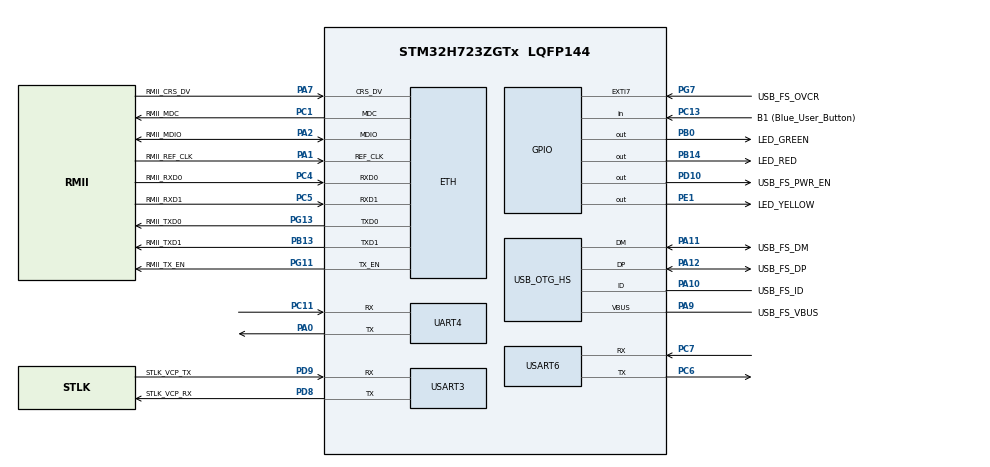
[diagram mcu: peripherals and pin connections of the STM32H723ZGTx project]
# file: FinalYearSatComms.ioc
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ETH.MediaInterface=HAL_ETH_RMII_MODE
Mcu.Family=STM32H7
Mcu.Name=STM32H723ZGTx
Mcu.Package=LQFP144
NVIC.PriorityGroup=NVIC_PRIORITYGROUP_4
PA0.Mode=Asynchronous
PA0.Signal=UART4_TX
PA1.GPIO_Label=RMII_REF_CLK
PA1.Mode=RMII
PA1.Signal=ETH_REF_CLK
PA10.GPIO_Label=USB_FS_ID
PA10.Mode=OTG/Dual-Role-Device-FS
PA10.Signal=USB_OTG_HS_ID
PA11.GPIO_Label=USB_FS_DM
PA11.Mode=OTG/Dual-Role-Device-FS
PA11.Signal=USB_OTG_HS_DM
PA12.GPIO_Label=USB_FS_DP
PA12.Mode=OTG/Dual-Role-Device-FS
PA12.Signal=USB_OTG_HS_DP
PA13(JTMS/SWDIO).GPIO_Label=SWDIO
PA13(JTMS/SWDIO).Mode=Trace_Asynchronous_SW
PA13(JTMS/SWDIO).Signal=DEBUG_JTMS-SWDIO
PA14(JTCK/SWCLK).GPIO_Label=SWCLK
PA14(JTCK/SWCLK).Mode=Trace_Asynchronous_SW
PA14(JTCK/SWCLK).Signal=DEBUG_JTCK-SWCLK
PA2.GPIO_Label=RMII_MDIO
PA2.Mode=RMII
PA2.Signal=ETH_MDIO
PA7.GPIO_Label=RMII_CRS_DV
PA7.Mode=RMII
PA7.Signal=ETH_CRS_DV
PA9.GPIO_Label=USB_FS_VBUS
PA9.Mode=Activate_VBUS_FS
PA9.Signal=USB_OTG_HS_VBUS
PB0.GPIO_Label=LED_GREEN
PB0.Signal=GPIO_Output
PB13.GPIO_Label=RMII_TXD1
PB13.Mode=RMII
PB13.Signal=ETH_TXD1
PB14.GPIO_Label=LED_RED
PB14.Signal=GPIO_Output
PB3(JTDO/TRACESWO).GPIO_Label=SWO
PB3(JTDO/TRACESWO).Mode=Trace_Asynchronous_SW
PB3(JTDO/TRACESWO).Signal=DEBUG_JTDO-SWO
PC1.GPIO_Label=RMII_MDC
PC1.Mode=RMII
PC1.Signal=ETH_MDC
PC11.Mode=Asynchronous
PC11.Signal=UART4_RX
PC13.GPIO_Label=B1 (Blue_User_Button)
PC13.Signal=GPIO_Input
PC14-OSC32_IN.Mode=LSE-External-Oscillator
PC14-OSC32_IN.Signal=RCC_OSC32_IN
PC15-OSC32_OUT.Mode=LSE-External-Oscillator
PC15-OSC32_OUT.Signal=RCC_OSC32_OUT
PC4.GPIO_Label=RMII_RXD0
PC4.Mode=RMII
PC4.Signal=ETH_RXD0
PC5.GPIO_Label=RMII_RXD1
PC5.Mode=RMII
PC5.Signal=ETH_RXD1
PC6.Mode=Asynchronous
PC6.Signal=USART6_TX
PC7.Mode=Asynchronous
PC7.Signal=USART6_RX
PD10.GPIO_Label=USB_FS_PWR_EN
PD10.Signal=GPIO_Output
PD8.GPIO_Label=STLK_VCP_RX
PD8.Mode=Asynchronous
PD8.Signal=USART3_TX
PD9.GPIO_Label=STLK_VCP_TX
PD9.Mode=Asynchronous
PD9.Signal=USART3_RX
PE1.GPIO_Label=LED_YELLOW
PE1.Signal=GPIO_Output
PG11.GPIO_Label=RMII_TX_EN
PG11.Mode=RMII
PG11.Signal=ETH_TX_EN
PG13.GPIO_Label=RMII_TXD0
PG13.Mode=RMII
PG13.Signal=ETH_TXD0
PG7.GPIO_Label=USB_FS_OVCR
PG7.Signal=GPXTI7
PH0-OSC_IN.GPIO_Label=MCO
PH0-OSC_IN.Mode=HSE-External-Oscillator
PH0-OSC_IN.Signal=RCC_OSC_IN
PH1-OSC_OUT.Mode=HSE-External-Oscillator
PH1-OSC_OUT.Signal=RCC_OSC_OUT
ProjectManager.HeapSize=0x200
ProjectManager.StackSize=0x400
ProjectManager.TargetToolchain=STM32CubeIDE
RCC.ADCFreq_Value=76000000
RCC.APB1Freq_Value=2000000
RCC.APB2Freq_Value=2000000
RCC.APB3Freq_Value=2000000
RCC.APB4Freq_Value=2000000
RCC.CortexFreq_Value=8000000
RCC.D1CPRE=1
RCC.D1PPRE=RCC_APB3_DIV2
RCC.D2PPRE1=RCC_APB1_DIV2
RCC.D2PPRE2=RCC_APB2_DIV2
RCC.D3PPRE=RCC_APB4_DIV2
RCC.DIVM2=1
RCC.DIVN2=19
RCC.DIVQ1=4
RCC.HCLKFreq_Value=4000000
RCC.HPRE=RCC_HCLK_DIV2
RCC.HSE_VALUE=8000000
RCC.PLL2FRACN=0
RCC.PLL3FRACN=0
RCC.SYSCLKFreq_VALUE=8000000
RCC.SYSCLKSource=RCC_SYSCLKSOURCE_PLLCLK
RCC.USBCLockSelection=RCC_USBCLKSOURCE_HSI48
RCC.USBFreq_Value=48000000
USART3.VirtualMode-Asynchronous=VM_ASYNC
USART6.VirtualMode-Asynchronous=VM_ASYNC
board=NUCLEO-H723ZG

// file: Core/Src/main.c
/* USER CODE BEGIN Header */
/**
  ******************************************************************************
  * @file           : main.c
  * @brief          : Main program body
  ******************************************************************************
  * @attention
  *
  * Copyright (c) 2024 STMicroelectronics.
  * All rights reserved.
  *
  * This software is licensed under terms that can be found in the LICENSE file
  * in the root directory of this software component.
  * If no LICENSE file comes with this software, it is provided AS-IS.
  *
  ******************************************************************************
  */
/* USER CODE END Header */
#include "main.h"
#include "string.h"
#include "stdio.h"
#if defined ( __ICCARM__ ) /*!< IAR Compiler */
#pragma location=0x30000000
ETH_DMADescTypeDef  DMARxDscrTab[ETH_RX_DESC_CNT]; /* Ethernet Rx DMA Descriptors */
#pragma location=0x30000200
ETH_DMADescTypeDef  DMATxDscrTab[ETH_TX_DESC_CNT]; /* Ethernet Tx DMA Descriptors */

#elif defined ( __CC_ARM )  /* MDK ARM Compiler */

__attribute__((at(0x30000000))) ETH_DMADescTypeDef  DMARxDscrTab[ETH_RX_DESC_CNT]; /* Ethernet Rx DMA Descriptors */
__attribute__((at(0x30000200))) ETH_DMADescTypeDef  DMATxDscrTab[ETH_TX_DESC_CNT]; /* Ethernet Tx DMA Descriptors */

#elif defined ( __GNUC__ ) /* GNU Compiler */

ETH_DMADescTypeDef DMARxDscrTab[ETH_RX_DESC_CNT] __attribute__((section(".RxDecripSection"))); /* Ethernet Rx DMA Descriptors */
ETH_DMADescTypeDef DMATxDscrTab[ETH_TX_DESC_CNT] __attribute__((section(".TxDecripSection")));   /* Ethernet Tx DMA Descriptors */
#endif

ETH_TxPacketConfig TxConfig;

ETH_HandleTypeDef heth;

UART_HandleTypeDef huart4;
UART_HandleTypeDef huart3;
UART_HandleTypeDef huart6;

void SystemClock_Config(void);
static void MX_GPIO_Init(void);
static void MX_ETH_Init(void);
static void MX_USART3_UART_Init(void);
static void MX_USB_OTG_HS_USB_Init(void);
static void MX_UART4_Init(void);
static void MX_USART6_UART_Init(void);

int _write(int file,char *ptr, int len)
{
	int i=0;
	for (i=0; i<len;i++)
		ITM_SendChar((*ptr++));
	return len;
}
uint8_t Data=0;
int main(void)
{

  HAL_Init();

  SystemClock_Config();

  MX_GPIO_Init();
  MX_ETH_Init();
  MX_USART3_UART_Init();
  MX_USB_OTG_HS_USB_Init();
  MX_UART4_Init();
  MX_USART6_UART_Init();

  while (1)
  {
	  printf("%d\n",Data);
	  Data++;
	  HAL_Delay(1000);
  }
  /* USER CODE END 3 */
}

void SystemClock_Config(void)
{
  RCC_OscInitTypeDef RCC_OscInitStruct = {0};
  RCC_ClkInitTypeDef RCC_ClkInitStruct = {0};

  /** Supply configuration update enable
  */
  HAL_PWREx_ConfigSupply(PWR_LDO_SUPPLY);

  /** Configure the main internal regulator output voltage
  */
  __HAL_PWR_VOLTAGESCALING_CONFIG(PWR_REGULATOR_VOLTAGE_SCALE3);

  while(!__HAL_PWR_GET_FLAG(PWR_FLAG_VOSRDY)) {}

  /** Initializes the RCC Oscillators according to the specified parameters
  * in the RCC_OscInitTypeDef structure.
  */
  RCC_OscInitStruct.OscillatorType = RCC_OSCILLATORTYPE_HSI48|RCC_OSCILLATORTYPE_HSI;
  RCC_OscInitStruct.HSIState = RCC_HSI_DIV1;
  RCC_OscInitStruct.HSICalibrationValue = 64;
  RCC_OscInitStruct.HSI48State = RCC_HSI48_ON;
  RCC_OscInitStruct.PLL.PLLState = RCC_PLL_ON;
  RCC_OscInitStruct.PLL.PLLSource = RCC_PLLSOURCE_HSI;
  RCC_OscInitStruct.PLL.PLLM = 32;
  RCC_OscInitStruct.PLL.PLLN = 129;
  RCC_OscInitStruct.PLL.PLLP = 2;
  RCC_OscInitStruct.PLL.PLLQ = 4;
  RCC_OscInitStruct.PLL.PLLR = 2;
  RCC_OscInitStruct.PLL.PLLRGE = RCC_PLL1VCIRANGE_1;
  RCC_OscInitStruct.PLL.PLLVCOSEL = RCC_PLL1VCOWIDE;
  RCC_OscInitStruct.PLL.PLLFRACN = 0;
  if (HAL_RCC_OscConfig(&RCC_OscInitStruct) != HAL_OK)
  {
    Error_Handler();
  }

  /** Initializes the CPU, AHB and APB buses clocks
  */
  RCC_ClkInitStruct.ClockType = RCC_CLOCKTYPE_HCLK|RCC_CLOCKTYPE_SYSCLK
                              |RCC_CLOCKTYPE_PCLK1|RCC_CLOCKTYPE_PCLK2
                              |RCC_CLOCKTYPE_D3PCLK1|RCC_CLOCKTYPE_D1PCLK1;
  RCC_ClkInitStruct.SYSCLKSource = RCC_SYSCLKSOURCE_PLLCLK;
  RCC_ClkInitStruct.SYSCLKDivider = 1;
  RCC_ClkInitStruct.AHBCLKDivider = RCC_HCLK_DIV2;
  RCC_ClkInitStruct.APB3CLKDivider = RCC_APB3_DIV2;
  RCC_ClkInitStruct.APB1CLKDivider = RCC_APB1_DIV2;
  RCC_ClkInitStruct.APB2CLKDivider = RCC_APB2_DIV2;
  RCC_ClkInitStruct.APB4CLKDivider = RCC_APB4_DIV2;

  if (HAL_RCC_ClockConfig(&RCC_ClkInitStruct, FLASH_LATENCY_0) != HAL_OK)
  {
    Error_Handler();
  }
}

static void MX_ETH_Init(void)
{

   static uint8_t MACAddr[6];

  heth.Instance = ETH;
  MACAddr[0] = 0x00;
  MACAddr[1] = 0x80;
  MACAddr[2] = 0xE1;
  MACAddr[3] = 0x00;
  MACAddr[4] = 0x00;
  MACAddr[5] = 0x00;
  heth.Init.MACAddr = &MACAddr[0];
  heth.Init.MediaInterface = HAL_ETH_RMII_MODE;
  heth.Init.TxDesc = DMATxDscrTab;
  heth.Init.RxDesc = DMARxDscrTab;
  heth.Init.RxBuffLen = 1524;

  if (HAL_ETH_Init(&heth) != HAL_OK)
  {
    Error_Handler();
  }

  memset(&TxConfig, 0 , sizeof(ETH_TxPacketConfig));
  TxConfig.Attributes = ETH_TX_PACKETS_FEATURES_CSUM | ETH_TX_PACKETS_FEATURES_CRCPAD;
  TxConfig.ChecksumCtrl = ETH_CHECKSUM_IPHDR_PAYLOAD_INSERT_PHDR_CALC;
  TxConfig.CRCPadCtrl = ETH_CRC_PAD_INSERT;

}

static void MX_UART4_Init(void)
{

  huart4.Instance = UART4;
  huart4.Init.BaudRate = 115200;
  huart4.Init.WordLength = UART_WORDLENGTH_8B;
  huart4.Init.StopBits = UART_STOPBITS_1;
  huart4.Init.Parity = UART_PARITY_NONE;
  huart4.Init.Mode = UART_MODE_TX_RX;
  huart4.Init.HwFlowCtl = UART_HWCONTROL_NONE;
  huart4.Init.OverSampling = UART_OVERSAMPLING_16;
  huart4.Init.OneBitSampling = UART_ONE_BIT_SAMPLE_DISABLE;
  huart4.Init.ClockPrescaler = UART_PRESCALER_DIV1;
  huart4.AdvancedInit.AdvFeatureInit = UART_ADVFEATURE_NO_INIT;
  if (HAL_UART_Init(&huart4) != HAL_OK)
  {
    Error_Handler();
  }
  if (HAL_UARTEx_SetTxFifoThreshold(&huart4, UART_TXFIFO_THRESHOLD_1_8) != HAL_OK)
  {
    Error_Handler();
  }
  if (HAL_UARTEx_SetRxFifoThreshold(&huart4, UART_RXFIFO_THRESHOLD_1_8) != HAL_OK)
  {
    Error_Handler();
  }
  if (HAL_UARTEx_DisableFifoMode(&huart4) != HAL_OK)
  {
    Error_Handler();
  }

}

static void MX_USART3_UART_Init(void)
{

  huart3.Instance = USART3;
  huart3.Init.BaudRate = 115200;
  huart3.Init.WordLength = UART_WORDLENGTH_8B;
  huart3.Init.StopBits = UART_STOPBITS_1;
  huart3.Init.Parity = UART_PARITY_NONE;
  huart3.Init.Mode = UART_MODE_TX_RX;
  huart3.Init.HwFlowCtl = UART_HWCONTROL_NONE;
  huart3.Init.OverSampling = UART_OVERSAMPLING_16;
  huart3.Init.OneBitSampling = UART_ONE_BIT_SAMPLE_DISABLE;
  huart3.Init.ClockPrescaler = UART_PRESCALER_DIV1;
  huart3.AdvancedInit.AdvFeatureInit = UART_ADVFEATURE_NO_INIT;
  if (HAL_UART_Init(&huart3) != HAL_OK)
  {
    Error_Handler();
  }
  if (HAL_UARTEx_SetTxFifoThreshold(&huart3, UART_TXFIFO_THRESHOLD_1_8) != HAL_OK)
  {
    Error_Handler();
  }
  if (HAL_UARTEx_SetRxFifoThreshold(&huart3, UART_RXFIFO_THRESHOLD_1_8) != HAL_OK)
  {
    Error_Handler();
  }
  if (HAL_UARTEx_DisableFifoMode(&huart3) != HAL_OK)
  {
    Error_Handler();
  }

}

static void MX_USART6_UART_Init(void)
{

  huart6.Instance = USART6;
  huart6.Init.BaudRate = 115200;
  huart6.Init.WordLength = UART_WORDLENGTH_8B;
  huart6.Init.StopBits = UART_STOPBITS_1;
  huart6.Init.Parity = UART_PARITY_NONE;
  huart6.Init.Mode = UART_MODE_TX_RX;
  huart6.Init.HwFlowCtl = UART_HWCONTROL_NONE;
  huart6.Init.OverSampling = UART_OVERSAMPLING_16;
  huart6.Init.OneBitSampling = UART_ONE_BIT_SAMPLE_DISABLE;
  huart6.Init.ClockPrescaler = UART_PRESCALER_DIV1;
  huart6.AdvancedInit.AdvFeatureInit = UART_ADVFEATURE_NO_INIT;
  if (HAL_UART_Init(&huart6) != HAL_OK)
  {
    Error_Handler();
  }
  if (HAL_UARTEx_SetTxFifoThreshold(&huart6, UART_TXFIFO_THRESHOLD_1_8) != HAL_OK)
  {
    Error_Handler();
  }
  if (HAL_UARTEx_SetRxFifoThreshold(&huart6, UART_RXFIFO_THRESHOLD_1_8) != HAL_OK)
  {
    Error_Handler();
  }
  if (HAL_UARTEx_DisableFifoMode(&huart6) != HAL_OK)
  {
    Error_Handler();
  }

}

static void MX_USB_OTG_HS_USB_Init(void)
{

}

static void MX_GPIO_Init(void)
{
  GPIO_InitTypeDef GPIO_InitStruct = {0};

  /* GPIO Ports Clock Enable */
  __HAL_RCC_GPIOC_CLK_ENABLE();
  __HAL_RCC_GPIOH_CLK_ENABLE();
  __HAL_RCC_GPIOA_CLK_ENABLE();
  __HAL_RCC_GPIOB_CLK_ENABLE();
  __HAL_RCC_GPIOD_CLK_ENABLE();
  __HAL_RCC_GPIOG_CLK_ENABLE();
  __HAL_RCC_GPIOE_CLK_ENABLE();

  /*Configure GPIO pin Output Level */
  HAL_GPIO_WritePin(GPIOB, LED_GREEN_Pin|LED_RED_Pin, GPIO_PIN_RESET);

  /*Configure GPIO pin Output Level */
  HAL_GPIO_WritePin(USB_FS_PWR_EN_GPIO_Port, USB_FS_PWR_EN_Pin, GPIO_PIN_RESET);

  /*Configure GPIO pin Output Level */
  HAL_GPIO_WritePin(LED_YELLOW_GPIO_Port, LED_YELLOW_Pin, GPIO_PIN_RESET);

  /*Configure GPIO pin : B1_Pin */
  GPIO_InitStruct.Pin = B1_Pin;
  GPIO_InitStruct.Mode = GPIO_MODE_INPUT;
  GPIO_InitStruct.Pull = GPIO_NOPULL;
  HAL_GPIO_Init(B1_GPIO_Port, &GPIO_InitStruct);

  /*Configure GPIO pins : LED_GREEN_Pin LED_RED_Pin */
  GPIO_InitStruct.Pin = LED_GREEN_Pin|LED_RED_Pin;
  GPIO_InitStruct.Mode = GPIO_MODE_OUTPUT_PP;
  GPIO_InitStruct.Pull = GPIO_NOPULL;
  GPIO_InitStruct.Speed = GPIO_SPEED_FREQ_LOW;
  HAL_GPIO_Init(GPIOB, &GPIO_InitStruct);

  /*Configure GPIO pin : USB_FS_PWR_EN_Pin */
  GPIO_InitStruct.Pin = USB_FS_PWR_EN_Pin;
  GPIO_InitStruct.Mode = GPIO_MODE_OUTPUT_PP;
  GPIO_InitStruct.Pull = GPIO_NOPULL;
  GPIO_InitStruct.Speed = GPIO_SPEED_FREQ_LOW;
  HAL_GPIO_Init(USB_FS_PWR_EN_GPIO_Port, &GPIO_InitStruct);

  /*Configure GPIO pin : USB_FS_OVCR_Pin */
  GPIO_InitStruct.Pin = USB_FS_OVCR_Pin;
  GPIO_InitStruct.Mode = GPIO_MODE_IT_RISING;
  GPIO_InitStruct.Pull = GPIO_NOPULL;
  HAL_GPIO_Init(USB_FS_OVCR_GPIO_Port, &GPIO_InitStruct);

  /*Configure GPIO pin : USB_FS_VBUS_Pin */
  GPIO_InitStruct.Pin = USB_FS_VBUS_Pin;
  GPIO_InitStruct.Mode = GPIO_MODE_INPUT;
  GPIO_InitStruct.Pull = GPIO_NOPULL;
  HAL_GPIO_Init(USB_FS_VBUS_GPIO_Port, &GPIO_InitStruct);

  /*Configure GPIO pin : USB_FS_ID_Pin */
  GPIO_InitStruct.Pin = USB_FS_ID_Pin;
  GPIO_InitStruct.Mode = GPIO_MODE_AF_PP;
  GPIO_InitStruct.Pull = GPIO_NOPULL;
  GPIO_InitStruct.Speed = GPIO_SPEED_FREQ_LOW;
  GPIO_InitStruct.Alternate = GPIO_AF10_OTG1_HS;
  HAL_GPIO_Init(USB_FS_ID_GPIO_Port, &GPIO_InitStruct);

  /*Configure GPIO pin : LED_YELLOW_Pin */
  GPIO_InitStruct.Pin = LED_YELLOW_Pin;
  GPIO_InitStruct.Mode = GPIO_MODE_OUTPUT_PP;
  GPIO_InitStruct.Pull = GPIO_NOPULL;
  GPIO_InitStruct.Speed = GPIO_SPEED_FREQ_LOW;
  HAL_GPIO_Init(LED_YELLOW_GPIO_Port, &GPIO_InitStruct);

}

void Error_Handler(void)
{
  __disable_irq();
  while (1)
  {
  }
}
